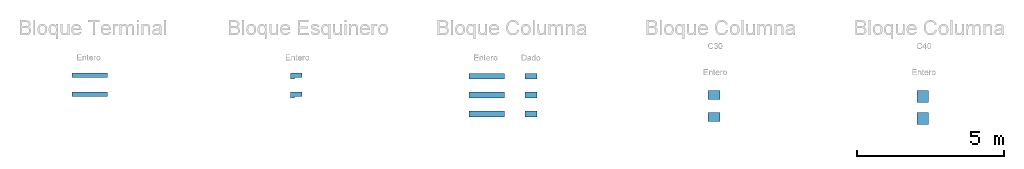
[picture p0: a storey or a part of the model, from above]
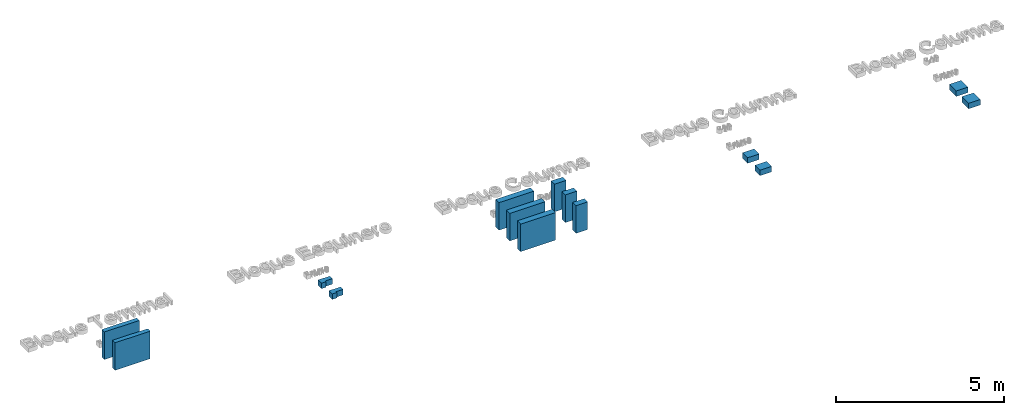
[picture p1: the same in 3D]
Properties of the parts of a building model (IFC2X3)

# File
Description: ViewDefinition [CoordinationView_V2.0]
File name: Versión 1.0
Time: 2025-05-08T22:19:15
Written by: The EXPRESS Data Manager Version 5.02.0100.07 : 28 Aug 2013
Made in: 21.0.0.383 - Exporter 21.0.0.383 - IU alternativa 21.0.0.383
Comment: STEP Physical File produced by: The EXPRESS Data Manager Version 5.02.0100.07 : 28 Aug 2013 * Module: EDMstepFileFactory/EDMstandAlone * Creation date: Thu May 08 22:19:15 2025 * Host: MSI * Database: C:\Users\valem\AppData\Local\Temp\0c03b512-117e-4236-a8f6-5f3e5b4cf95f\e787f376-32e3-4956-90a1-744972cd3e90\ifc * Database version: 5507 * Database creation date: Thu May 08 22:19:03 2025 * Schema: IFC2X3 * Model: DataRepository.ifc * Model creation date: Thu May 08 22:19:03 2025 * Header model: DataRepository.ifc_HeaderModel * Header model creation date: Thu May 08 22:19:03 2025 * EDMuser: sdai-user * EDMgroup: sdai-group * License ID and type: 5605 : Permanent license. Expiry date: * EDMstepFileFactory options: 020000

# IfcProject, Versión 1.0
LongName: Template Complementos de La Peña; Phase: Prototipo

# IfcSite, Default
RefLatitude: 40, 25, 13, 9643; RefLongitude: -3, -42, -20, -772056; RefElevation: 0 m

# IfcBuilding
Pset_BuildingCommon - NumberOfStoreys: 1

# IfcBuildingStorey: Nivel:Nivel 1, Nivel 1
LongName: Nivel 1; Elevation: 0 m

# IfcBuildingElementProxy: Texto de modelo:Subtítulo (8)
In: Nivel 1
Type - Pset_BuildingElementProxyCommon - Reference: Subtítulo
Type - Pset_QuantityTakeOff - Reference: Subtítulo
Pset_BuildingElementProxyCommon - sets with these values: 2
Pset_ProvisionForVoid - Shape: Undefined; Width: 0.15 m; Depth: 0.15 m
Name (Texto de modelo:Subtítulo:...)
163547
163549
163553
163558
163559
163560
163561
163562

# IfcBuildingElementProxy: Texto de modelo:Título (5)
In: Nivel 1
Type - Pset_BuildingElementProxyCommon - Reference: Título
Type - Pset_QuantityTakeOff - Reference: Título
Pset_BuildingElementProxyCommon - sets with these values: 2
Pset_ProvisionForVoid - Shape: Undefined; Width: 0.15 m; Depth: 0.15 m
Name (Texto de modelo:Título:...) | Height (m)
163546 | 0.502282
163548 | 0.0627852
163550 | 0.502282
163551 | 0.502282
163552 | 0.502282

# IfcWall: Bloque esquinero1:Bloque esquinero, Bloque esquinero1:Bloque esquinero:163590
In: Nivel 1
Type - Material: Bloque esquinero - Rosado
Type - Pset_ManufacturerTypeInformation - Manufacturer: Bloques de la Peña
Type - Pset_QuantityTakeOff - Reference: Bloque esquinero
Type - Pset_ReinforcementBarPitchOfWall - Reference: Bloque esquinero
Type - Pset_WallCommon - IsExternal: no; Reference: Bloque esquinero
Pset_QuantityTakeOff - sets with these values: 2

# IfcWall: Bloque esquinero2:Bloque esquinero, Bloque esquinero2:Bloque esquinero:163610
In: Nivel 1
Type - Material: Bloque Columna (30) - Natural
Type - Pset_ManufacturerTypeInformation - Manufacturer: Bloques de la Peña
Type - Pset_QuantityTakeOff - Reference: Bloque esquinero
Type - Pset_ReinforcementBarPitchOfWall - Reference: Bloque esquinero
Type - Pset_WallCommon - IsExternal: no; Reference: Bloque esquinero
Pset_QuantityTakeOff - sets with these values: 2

# IfcWall: Bloque esquinero3:Bloque esquinero, Bloque esquinero3:Bloque esquinero:163622
In: Nivel 1
Type - Material: Bloque Columna (30) - Rosado
Type - Pset_ManufacturerTypeInformation - Manufacturer: Bloques de la Peña
Type - Pset_QuantityTakeOff - Reference: Bloque esquinero
Type - Pset_ReinforcementBarPitchOfWall - Reference: Bloque esquinero
Type - Pset_WallCommon - IsExternal: no; Reference: Bloque esquinero
Pset_QuantityTakeOff - sets with these values: 2

# IfcWall: Bloque esquinero4:Bloque esquinero, Bloque esquinero4:Bloque esquinero:163634
In: Nivel 1
Type - Material: Bloque esquinero - Natural
Type - Pset_ManufacturerTypeInformation - Manufacturer: Bloques de la Peña
Type - Pset_QuantityTakeOff - Reference: Bloque esquinero
Type - Pset_ReinforcementBarPitchOfWall - Reference: Bloque esquinero
Type - Pset_WallCommon - IsExternal: no; Reference: Bloque esquinero
Pset_QuantityTakeOff - sets with these values: 2

# IfcWall: Bloque esquinero5:Bloque esquinero, Bloque esquinero5:Bloque esquinero:163646
In: Nivel 1
Type - Material: Bloque Columna (40) - Rosado
Type - Pset_ManufacturerTypeInformation - Manufacturer: Bloques de la Peña
Type - Pset_QuantityTakeOff - Reference: Bloque esquinero
Type - Pset_ReinforcementBarPitchOfWall - Reference: Bloque esquinero
Type - Pset_WallCommon - IsExternal: no; Reference: Bloque esquinero
Pset_QuantityTakeOff - sets with these values: 2

# IfcWall: Bloque esquinero:Bloque esquinero, Bloque esquinero:Bloque esquinero:163576
In: Nivel 1
Type - Material: Bloque esquinero - Natural
Type - Pset_ManufacturerTypeInformation - Manufacturer: Bloques de la Peña
Type - Pset_QuantityTakeOff - Reference: Bloque esquinero
Type - Pset_ReinforcementBarPitchOfWall - Reference: Bloque esquinero
Type - Pset_WallCommon - IsExternal: no; Reference: Bloque esquinero
Pset_QuantityTakeOff - sets with these values: 2

# IfcWallStandardCase: Muro básico:Bloque Columna (Entero) - Natural, Muro básico:Bloque Columna (Entero) - Natural:163554
In: Nivel 1
Type - PredefinedType: STANDARD; Material: Bloque Columna (Entero) - Natural 0.2 m
Type - Pset_ManufacturerTypeInformation - Manufacturer: Bloques de la Peña
Type - Pset_QuantityTakeOff - Reference: Bloque Columna (Entero) - Natural
Type - Pset_ReinforcementBarPitchOfWall - Reference: Bloque Columna (Entero) - Natural
Type - Pset_WallCommon - IsExternal: no; Reference: Bloque Columna (Entero) - Natural
Pset_QuantityTakeOff - sets with these values: 2
Pset_WallCommon - ExtendToStructure: no; LoadBearing: no

# IfcWallStandardCase: Muro básico:Bloque Columna (Entero) - Rojo, Muro básico:Bloque Columna (Entero) - Rojo:163595
In: Nivel 1
Type - PredefinedType: STANDARD; Material: Bloque Columna (Entero) - Rojo 0.2 m
Type - Pset_ManufacturerTypeInformation - Manufacturer: Bloques de la Peña
Type - Pset_QuantityTakeOff - Reference: Bloque Columna (Entero) - Rojo
Type - Pset_ReinforcementBarPitchOfWall - Reference: Bloque Columna (Entero) - Rojo
Type - Pset_WallCommon - IsExternal: no; Reference: Bloque Columna (Entero) - Rojo
Pset_QuantityTakeOff - sets with these values: 2
Pset_WallCommon - ExtendToStructure: no; LoadBearing: no

# IfcWallStandardCase: Muro básico:Bloque Columna (Entero) - Rosado, Muro básico:Bloque Columna (Entero) - Rosado:163591
In: Nivel 1
Type - PredefinedType: STANDARD; Material: Bloque Columna (Entero) - Rosado 0.2 m
Type - Pset_ManufacturerTypeInformation - Manufacturer: Bloques de la Peña
Type - Pset_QuantityTakeOff - Reference: Bloque Columna (Entero) - Rosado
Type - Pset_ReinforcementBarPitchOfWall - Reference: Bloque Columna (Entero) - Rosado
Type - Pset_WallCommon - IsExternal: no; Reference: Bloque Columna (Entero) - Rosado
Pset_QuantityTakeOff - sets with these values: 2
Pset_WallCommon - ExtendToStructure: no; LoadBearing: no

# IfcWallStandardCase: Muro básico:Bloque columna (Mitad) - Natural, Muro básico:Bloque columna (Mitad) - Natural:163556
In: Nivel 1
Type - PredefinedType: STANDARD; Material: Bloque Columna (Mitad) - Natural 0.2 m
Type - Pset_ManufacturerTypeInformation - Manufacturer: Bloques de la Peña
Type - Pset_QuantityTakeOff - Reference: Bloque columna (Mitad) - Natural
Type - Pset_ReinforcementBarPitchOfWall - Reference: Bloque columna (Mitad) - Natural
Type - Pset_WallCommon - IsExternal: no; Reference: Bloque columna (Mitad) - Natural
Pset_QuantityTakeOff - sets with these values: 2
Pset_WallCommon - ExtendToStructure: no; LoadBearing: no

# IfcWallStandardCase: Muro básico:Bloque columna (Mitad) - Rojo, Muro básico:Bloque columna (Mitad) - Rojo:163597
In: Nivel 1
Type - PredefinedType: STANDARD; Material: Bloque Columna (Mitad) - Rojo 0.2 m
Type - Pset_ManufacturerTypeInformation - Manufacturer: Bloques de la Peña
Type - Pset_QuantityTakeOff - Reference: Bloque columna (Mitad) - Rojo
Type - Pset_ReinforcementBarPitchOfWall - Reference: Bloque columna (Mitad) - Rojo
Type - Pset_WallCommon - IsExternal: no; Reference: Bloque columna (Mitad) - Rojo
Pset_QuantityTakeOff - sets with these values: 2
Pset_WallCommon - ExtendToStructure: no; LoadBearing: no

# IfcWallStandardCase: Muro básico:Bloque columna (Mitad) - Rosado, Muro básico:Bloque columna (Mitad) - Rosado:163593
In: Nivel 1
Type - PredefinedType: STANDARD; Material: Bloque Columna (Mitad) - Rosado 0.2 m
Type - Pset_ManufacturerTypeInformation - Manufacturer: Bloques de la Peña
Type - Pset_QuantityTakeOff - Reference: Bloque columna (Mitad) - Rosado
Type - Pset_ReinforcementBarPitchOfWall - Reference: Bloque columna (Mitad) - Rosado
Type - Pset_WallCommon - IsExternal: no; Reference: Bloque columna (Mitad) - Rosado
Pset_QuantityTakeOff - sets with these values: 2
Pset_WallCommon - ExtendToStructure: no; LoadBearing: no

# IfcWallStandardCase: Muro básico:Bloque terminal - Natural, Muro básico:Bloque terminal - Natural:163542
In: Nivel 1
Type - PredefinedType: STANDARD; Material: Bloque terminal - Natural 0.15 m
Type - Pset_ManufacturerTypeInformation - Manufacturer: Bloques de la Peña
Type - Pset_QuantityTakeOff - Reference: Bloque terminal - Natural
Type - Pset_ReinforcementBarPitchOfWall - Reference: Bloque terminal - Natural
Type - Pset_WallCommon - Reference: Bloque terminal - Natural; IsExternal: no
Pset_QuantityTakeOff - sets with these values: 2
Pset_WallCommon - ExtendToStructure: no; LoadBearing: no

# IfcWallStandardCase: Muro básico:Bloque terminal - Rosado, Muro básico:Bloque terminal - Rosado:163544
In: Nivel 1
Type - PredefinedType: STANDARD; Material: Bloque terminal - Rosado 0.15 m
Type - Pset_ManufacturerTypeInformation - Manufacturer: Bloques de la Peña
Type - Pset_QuantityTakeOff - Reference: Bloque terminal - Rosado
Type - Pset_ReinforcementBarPitchOfWall - Reference: Bloque terminal - Rosado
Type - Pset_WallCommon - IsExternal: no; Reference: Bloque terminal - Rosado
Pset_QuantityTakeOff - sets with these values: 2
Pset_WallCommon - ExtendToStructure: no; LoadBearing: no
